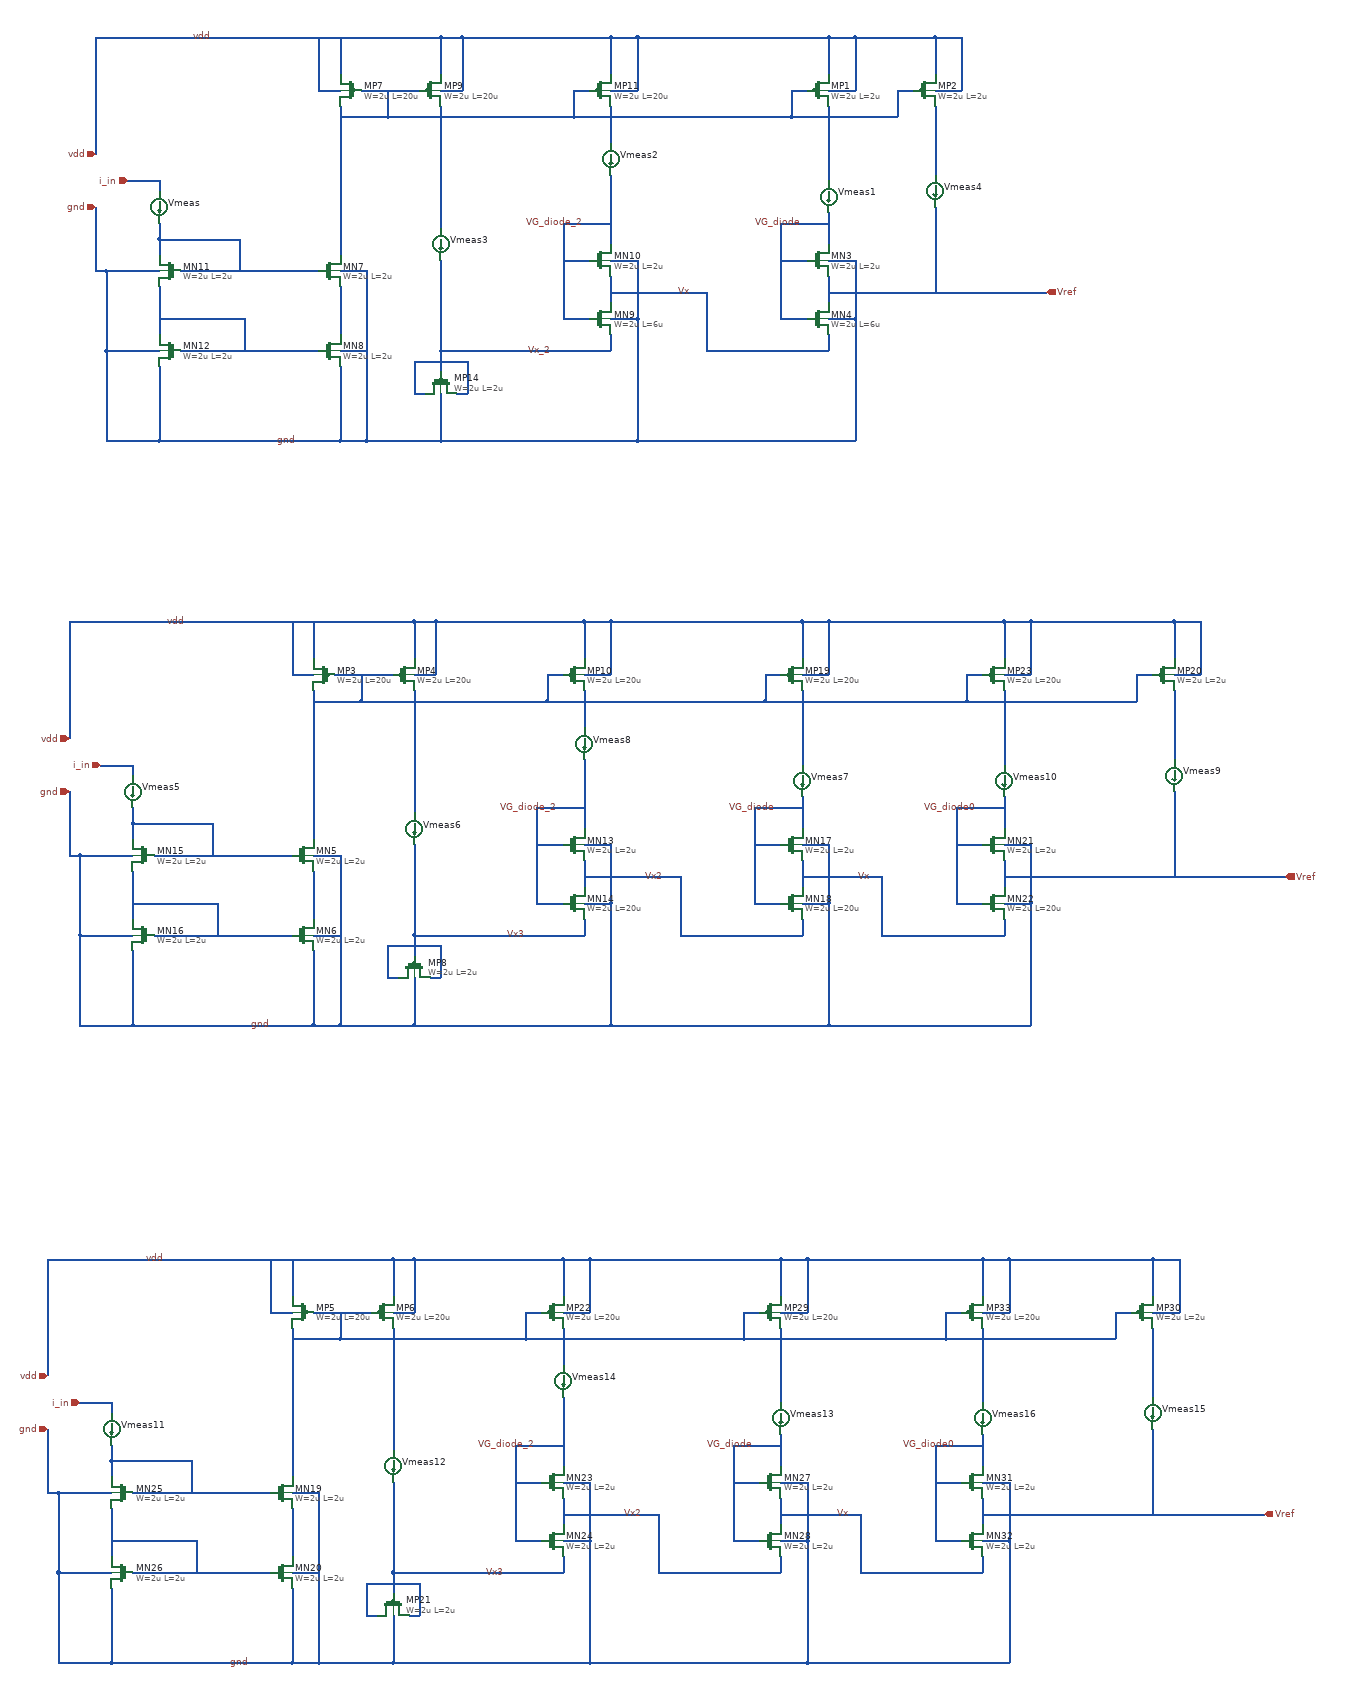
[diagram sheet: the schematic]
v {xschem version=3.4.0 file_version=1.2
}
G {}
K {}
V {}
S {}
E {}
N -300 -100 190 -100 {
lab=vdd}
N 190 -100 190 -30 {
lab=vdd}
N 0 -100 0 -30 {
lab=vdd}
N 40 0 150 0 {
lab=#net1}
N 0 30 0 90 {
lab=#net1}
N 190 30 190 90 {
lab=#net2}
N 90 0 90 40 {
lab=#net1}
N 90 40 90 50 {
lab=#net1}
N 0 50 90 50 {
lab=#net1}
N 0 150 0 310 {
lab=#net1}
N 0 370 0 460 {
lab=#net3}
N 0 520 0 660 {
lab=gnd}
N -260 660 0 660 {
lab=gnd}
N -300 340 -40 340 {
lab=#net4}
N -300 490 -40 490 {
lab=#net5}
N 0 340 50 340 {
lab=gnd}
N 50 340 50 660 {
lab=gnd}
N 0 660 50 660 {
lab=gnd}
N 0 490 50 490 {
lab=gnd}
N -40 0 0 0 {
lab=vdd}
N -40 -100 -40 0 {
lab=vdd}
N 190 0 230 0 {
lab=vdd}
N 230 -100 230 0 {
lab=vdd}
N 190 -100 230 -100 {
lab=vdd}
N 50 660 190 660 {
lab=gnd}
N 230 -100 510 -100 {
lab=vdd}
N 510 -100 510 -30 {
lab=vdd}
N 510 30 510 100 {
lab=#net6}
N 510 0 560 0 {
lab=vdd}
N 560 -100 560 0 {
lab=vdd}
N 510 -100 560 -100 {
lab=vdd}
N 440 0 470 0 {
lab=#net1}
N 440 0 440 50 {
lab=#net1}
N 420 430 470 430 {
lab=VG_diode_2}
N 420 250 420 430 {
lab=VG_diode_2}
N 420 250 510 250 {
lab=VG_diode_2}
N 420 320 470 320 {
lab=VG_diode_2}
N 510 350 510 400 {
lab=Vx}
N 510 460 510 490 {
lab=Vx_2}
N 190 660 560 660 {
lab=gnd}
N 510 430 560 430 {
lab=gnd}
N 510 320 560 320 {
lab=gnd}
N 560 320 560 430 {
lab=gnd}
N -340 370 -340 460 {
lab=#net5}
N -340 520 -340 660 {
lab=gnd}
N -340 660 -260 660 {
lab=gnd}
N -440 490 -340 490 {
lab=gnd}
N -440 490 -440 660 {
lab=gnd}
N -440 660 -340 660 {
lab=gnd}
N -440 340 -340 340 {
lab=gnd}
N -440 340 -440 490 {
lab=gnd}
N -340 -100 -300 -100 {
lab=vdd}
N -190 280 -190 340 {
lab=#net4}
N -340 280 -190 280 {
lab=#net4}
N -180 430 -180 490 {
lab=#net5}
N -340 430 -180 430 {
lab=#net5}
N 510 230 510 290 {
lab=VG_diode_2}
N -400 170 -340 170 {
lab=i_in}
N -460 -100 -460 120 {
lab=vdd}
N -460 -100 -340 -100 {
lab=vdd}
N -460 220 -460 340 {
lab=gnd}
N -460 340 -440 340 {
lab=gnd}
N -340 170 -340 190 {
lab=i_in}
N -340 250 -340 280 {
lab=#net4}
N -340 280 -340 310 {
lab=#net4}
N 190 150 190 260 {
lab=#net2}
N 190 320 190 490 {
lab=Vx_2}
N 190 490 190 530 {
lab=Vx_2}
N 220 570 240 570 {
lab=Vx_2}
N 240 510 240 570 {
lab=Vx_2}
N 190 510 240 510 {
lab=Vx_2}
N 140 570 160 570 {
lab=Vx_2}
N 140 510 140 570 {
lab=Vx_2}
N 140 510 190 510 {
lab=Vx_2}
N 190 570 190 660 {
lab=gnd}
N 90 50 440 50 {
lab=#net1}
N 920 -100 920 -30 {
lab=vdd}
N 920 30 920 100 {
lab=#net7}
N 920 0 970 0 {
lab=vdd}
N 970 -100 970 0 {
lab=vdd}
N 920 -100 970 -100 {
lab=vdd}
N 850 0 880 0 {
lab=#net1}
N 850 0 850 50 {
lab=#net1}
N 830 430 880 430 {
lab=VG_diode}
N 830 250 830 430 {
lab=VG_diode}
N 830 250 920 250 {
lab=VG_diode}
N 830 320 880 320 {
lab=VG_diode}
N 920 350 920 400 {
lab=Vref}
N 920 460 920 490 {
lab=Vx}
N 970 430 970 660 {
lab=gnd}
N 920 430 970 430 {
lab=gnd}
N 920 320 970 320 {
lab=gnd}
N 970 320 970 430 {
lab=gnd}
N 920 380 1330 380 {
lab=Vref}
N 920 150 920 170 {
lab=#net7}
N 920 230 920 290 {
lab=VG_diode}
N 440 50 850 50 {
lab=#net1}
N 190 490 510 490 {
lab=Vx_2}
N 560 430 560 660 {
lab=gnd}
N 560 660 970 660 {
lab=gnd}
N 690 490 920 490 {
lab=Vx}
N 690 380 690 490 {
lab=Vx}
N 510 380 690 380 {
lab=Vx}
N 510 160 510 230 {
lab=VG_diode_2}
N 190 90 190 150 {
lab=#net2}
N 0 90 0 140 {
lab=#net1}
N 0 140 0 150 {
lab=#net1}
N 920 100 920 150 {
lab=#net7}
N 560 -100 920 -100 {
lab=vdd}
N 1120 -100 1120 -30 {
lab=vdd}
N 1120 30 1120 100 {
lab=#net8}
N 1120 0 1170 0 {
lab=vdd}
N 1170 -100 1170 0 {
lab=vdd}
N 1120 -100 1170 -100 {
lab=vdd}
N 1050 0 1080 0 {
lab=#net1}
N 1050 0 1050 50 {
lab=#net1}
N 860 50 1050 50 {
lab=#net1}
N 850 50 860 50 {
lab=#net1}
N 970 -100 1120 -100 {
lab=vdd}
N 1120 100 1120 160 {
lab=#net8}
N 1120 220 1120 380 {
lab=Vref}
N -350 1000 140 1000 {
lab=vdd}
N 140 1000 140 1070 {
lab=vdd}
N -50 1000 -50 1070 {
lab=vdd}
N -10 1100 100 1100 {
lab=#net1}
N -50 1130 -50 1190 {
lab=#net1}
N 140 1130 140 1190 {
lab=#net2}
N 40 1100 40 1140 {
lab=#net1}
N 40 1140 40 1150 {
lab=#net1}
N -50 1150 40 1150 {
lab=#net1}
N -50 1250 -50 1410 {
lab=#net1}
N -50 1470 -50 1560 {
lab=#net3}
N -50 1620 -50 1760 {
lab=gnd}
N -310 1760 -50 1760 {
lab=gnd}
N -350 1440 -90 1440 {
lab=#net4}
N -350 1590 -90 1590 {
lab=#net5}
N -50 1440 0 1440 {
lab=gnd}
N 0 1440 0 1760 {
lab=gnd}
N -50 1760 0 1760 {
lab=gnd}
N -50 1590 0 1590 {
lab=gnd}
N -90 1100 -50 1100 {
lab=vdd}
N -90 1000 -90 1100 {
lab=vdd}
N 140 1100 180 1100 {
lab=vdd}
N 180 1000 180 1100 {
lab=vdd}
N 140 1000 180 1000 {
lab=vdd}
N 0 1760 140 1760 {
lab=gnd}
N 180 1000 460 1000 {
lab=vdd}
N 460 1000 460 1070 {
lab=vdd}
N 460 1130 460 1200 {
lab=#net6}
N 460 1100 510 1100 {
lab=vdd}
N 510 1000 510 1100 {
lab=vdd}
N 460 1000 510 1000 {
lab=vdd}
N 390 1100 420 1100 {
lab=#net1}
N 390 1100 390 1150 {
lab=#net1}
N 370 1530 420 1530 {
lab=VG_diode_2}
N 370 1350 370 1530 {
lab=VG_diode_2}
N 370 1350 460 1350 {
lab=VG_diode_2}
N 370 1420 420 1420 {
lab=VG_diode_2}
N 460 1450 460 1500 {
lab=Vx2}
N 460 1560 460 1590 {
lab=Vx3}
N 140 1760 510 1760 {
lab=gnd}
N 460 1530 510 1530 {
lab=gnd}
N 460 1420 510 1420 {
lab=gnd}
N 510 1420 510 1530 {
lab=gnd}
N -390 1470 -390 1560 {
lab=#net5}
N -390 1620 -390 1760 {
lab=gnd}
N -390 1760 -310 1760 {
lab=gnd}
N -490 1590 -390 1590 {
lab=gnd}
N -490 1590 -490 1760 {
lab=gnd}
N -490 1760 -390 1760 {
lab=gnd}
N -490 1440 -390 1440 {
lab=gnd}
N -490 1440 -490 1590 {
lab=gnd}
N -390 1000 -350 1000 {
lab=vdd}
N -240 1380 -240 1440 {
lab=#net4}
N -390 1380 -240 1380 {
lab=#net4}
N -230 1530 -230 1590 {
lab=#net5}
N -390 1530 -230 1530 {
lab=#net5}
N 460 1330 460 1390 {
lab=VG_diode_2}
N -450 1270 -390 1270 {
lab=i_in}
N -510 1000 -510 1220 {
lab=vdd}
N -510 1000 -390 1000 {
lab=vdd}
N -510 1320 -510 1440 {
lab=gnd}
N -510 1440 -490 1440 {
lab=gnd}
N -390 1270 -390 1290 {
lab=i_in}
N -390 1350 -390 1380 {
lab=#net4}
N -390 1380 -390 1410 {
lab=#net4}
N 140 1250 140 1360 {
lab=#net2}
N 140 1420 140 1590 {
lab=Vx3}
N 140 1590 140 1630 {
lab=Vx3}
N 170 1670 190 1670 {
lab=Vx3}
N 190 1610 190 1670 {
lab=Vx3}
N 140 1610 190 1610 {
lab=Vx3}
N 90 1670 110 1670 {
lab=Vx3}
N 90 1610 90 1670 {
lab=Vx3}
N 90 1610 140 1610 {
lab=Vx3}
N 140 1670 140 1760 {
lab=gnd}
N 40 1150 390 1150 {
lab=#net1}
N 870 1000 870 1070 {
lab=vdd}
N 870 1130 870 1200 {
lab=#net7}
N 870 1100 920 1100 {
lab=vdd}
N 920 1000 920 1100 {
lab=vdd}
N 870 1000 920 1000 {
lab=vdd}
N 800 1100 830 1100 {
lab=#net1}
N 800 1100 800 1150 {
lab=#net1}
N 780 1530 830 1530 {
lab=VG_diode}
N 780 1350 780 1530 {
lab=VG_diode}
N 780 1350 870 1350 {
lab=VG_diode}
N 780 1420 830 1420 {
lab=VG_diode}
N 870 1450 870 1500 {
lab=Vx}
N 870 1560 870 1590 {
lab=Vx2}
N 920 1530 920 1760 {
lab=gnd}
N 870 1530 920 1530 {
lab=gnd}
N 870 1420 920 1420 {
lab=gnd}
N 920 1420 920 1530 {
lab=gnd}
N 870 1250 870 1270 {
lab=#net7}
N 870 1330 870 1390 {
lab=VG_diode}
N 390 1150 800 1150 {
lab=#net1}
N 140 1590 460 1590 {
lab=Vx3}
N 510 1530 510 1760 {
lab=gnd}
N 510 1760 920 1760 {
lab=gnd}
N 640 1590 870 1590 {
lab=Vx2}
N 640 1480 640 1590 {
lab=Vx2}
N 460 1480 640 1480 {
lab=Vx2}
N 460 1260 460 1330 {
lab=VG_diode_2}
N 140 1190 140 1250 {
lab=#net2}
N -50 1190 -50 1240 {
lab=#net1}
N -50 1240 -50 1250 {
lab=#net1}
N 870 1200 870 1250 {
lab=#net7}
N 510 1000 870 1000 {
lab=vdd}
N 1570 1000 1570 1070 {
lab=vdd}
N 1570 1130 1570 1200 {
lab=#net8}
N 1570 1100 1620 1100 {
lab=vdd}
N 1620 1000 1620 1100 {
lab=vdd}
N 1570 1000 1620 1000 {
lab=vdd}
N 1500 1100 1530 1100 {
lab=#net1}
N 1500 1100 1500 1150 {
lab=#net1}
N 810 1150 1000 1150 {
lab=#net1}
N 800 1150 810 1150 {
lab=#net1}
N 920 1000 1070 1000 {
lab=vdd}
N 1570 1200 1570 1260 {
lab=#net8}
N 1570 1320 1570 1480 {
lab=Vref}
N 1020 1590 1250 1590 {
lab=Vx}
N 1020 1480 1020 1590 {
lab=Vx}
N 1300 1000 1450 1000 {
lab=vdd}
N 870 1480 1020 1480 {
lab=Vx}
N 920 1760 1300 1760 {
lab=gnd}
N 1070 1000 1250 1000 {
lab=vdd}
N 1000 1150 1180 1150 {
lab=#net1}
N 1450 1000 1570 1000 {
lab=vdd}
N 1380 1150 1500 1150 {
lab=#net1}
N 1250 1000 1250 1070 {
lab=vdd}
N 1250 1130 1250 1200 {
lab=#net9}
N 1250 1100 1300 1100 {
lab=vdd}
N 1300 1000 1300 1100 {
lab=vdd}
N 1250 1000 1300 1000 {
lab=vdd}
N 1180 1100 1210 1100 {
lab=#net1}
N 1180 1100 1180 1150 {
lab=#net1}
N 1160 1530 1210 1530 {
lab=VG_diode0}
N 1160 1350 1160 1530 {
lab=VG_diode0}
N 1160 1350 1250 1350 {
lab=VG_diode0}
N 1160 1420 1210 1420 {
lab=VG_diode0}
N 1250 1450 1250 1500 {
lab=Vref}
N 1250 1560 1250 1590 {
lab=Vx}
N 1300 1530 1300 1760 {
lab=gnd}
N 1250 1530 1300 1530 {
lab=gnd}
N 1250 1420 1300 1420 {
lab=gnd}
N 1300 1420 1300 1530 {
lab=gnd}
N 1250 1250 1250 1270 {
lab=#net9}
N 1250 1330 1250 1390 {
lab=VG_diode0}
N 1250 1200 1250 1250 {
lab=#net9}
N 1190 1150 1380 1150 {
lab=#net1}
N 1180 1150 1190 1150 {
lab=#net1}
N 1250 1480 1420 1480 {
lab=Vref}
N 1420 1480 1780 1480 {
lab=Vref}
N -390 2200 100 2200 {
lab=vdd}
N 100 2200 100 2270 {
lab=vdd}
N -90 2200 -90 2270 {
lab=vdd}
N -50 2300 60 2300 {
lab=#net1}
N -90 2330 -90 2390 {
lab=#net1}
N 100 2330 100 2390 {
lab=#net2}
N 0 2300 0 2340 {
lab=#net1}
N 0 2340 0 2350 {
lab=#net1}
N -90 2350 0 2350 {
lab=#net1}
N -90 2450 -90 2610 {
lab=#net1}
N -90 2670 -90 2760 {
lab=#net3}
N -90 2820 -90 2960 {
lab=gnd}
N -350 2960 -90 2960 {
lab=gnd}
N -390 2640 -130 2640 {
lab=#net4}
N -390 2790 -130 2790 {
lab=#net5}
N -90 2640 -40 2640 {
lab=gnd}
N -40 2640 -40 2960 {
lab=gnd}
N -90 2960 -40 2960 {
lab=gnd}
N -90 2790 -40 2790 {
lab=gnd}
N -130 2300 -90 2300 {
lab=vdd}
N -130 2200 -130 2300 {
lab=vdd}
N 100 2300 140 2300 {
lab=vdd}
N 140 2200 140 2300 {
lab=vdd}
N 100 2200 140 2200 {
lab=vdd}
N -40 2960 100 2960 {
lab=gnd}
N 140 2200 420 2200 {
lab=vdd}
N 420 2200 420 2270 {
lab=vdd}
N 420 2330 420 2400 {
lab=#net6}
N 420 2300 470 2300 {
lab=vdd}
N 470 2200 470 2300 {
lab=vdd}
N 420 2200 470 2200 {
lab=vdd}
N 350 2300 380 2300 {
lab=#net1}
N 350 2300 350 2350 {
lab=#net1}
N 330 2730 380 2730 {
lab=VG_diode_2}
N 330 2550 330 2730 {
lab=VG_diode_2}
N 330 2550 420 2550 {
lab=VG_diode_2}
N 330 2620 380 2620 {
lab=VG_diode_2}
N 420 2650 420 2700 {
lab=Vx2}
N 420 2760 420 2790 {
lab=Vx3}
N 100 2960 470 2960 {
lab=gnd}
N 420 2730 470 2730 {
lab=gnd}
N 420 2620 470 2620 {
lab=gnd}
N 470 2620 470 2730 {
lab=gnd}
N -430 2670 -430 2760 {
lab=#net5}
N -430 2820 -430 2960 {
lab=gnd}
N -430 2960 -350 2960 {
lab=gnd}
N -530 2790 -430 2790 {
lab=gnd}
N -530 2790 -530 2960 {
lab=gnd}
N -530 2960 -430 2960 {
lab=gnd}
N -530 2640 -430 2640 {
lab=gnd}
N -530 2640 -530 2790 {
lab=gnd}
N -430 2200 -390 2200 {
lab=vdd}
N -280 2580 -280 2640 {
lab=#net4}
N -430 2580 -280 2580 {
lab=#net4}
N -270 2730 -270 2790 {
lab=#net5}
N -430 2730 -270 2730 {
lab=#net5}
N 420 2530 420 2590 {
lab=VG_diode_2}
N -490 2470 -430 2470 {
lab=i_in}
N -550 2200 -550 2420 {
lab=vdd}
N -550 2200 -430 2200 {
lab=vdd}
N -550 2520 -550 2640 {
lab=gnd}
N -550 2640 -530 2640 {
lab=gnd}
N -430 2470 -430 2490 {
lab=i_in}
N -430 2550 -430 2580 {
lab=#net4}
N -430 2580 -430 2610 {
lab=#net4}
N 100 2450 100 2560 {
lab=#net2}
N 100 2620 100 2790 {
lab=Vx3}
N 100 2790 100 2830 {
lab=Vx3}
N 130 2870 150 2870 {
lab=Vx3}
N 150 2810 150 2870 {
lab=Vx3}
N 100 2810 150 2810 {
lab=Vx3}
N 50 2870 70 2870 {
lab=Vx3}
N 50 2810 50 2870 {
lab=Vx3}
N 50 2810 100 2810 {
lab=Vx3}
N 100 2870 100 2960 {
lab=gnd}
N 0 2350 350 2350 {
lab=#net1}
N 830 2200 830 2270 {
lab=vdd}
N 830 2330 830 2400 {
lab=#net7}
N 830 2300 880 2300 {
lab=vdd}
N 880 2200 880 2300 {
lab=vdd}
N 830 2200 880 2200 {
lab=vdd}
N 760 2300 790 2300 {
lab=#net1}
N 760 2300 760 2350 {
lab=#net1}
N 740 2730 790 2730 {
lab=VG_diode}
N 740 2550 740 2730 {
lab=VG_diode}
N 740 2550 830 2550 {
lab=VG_diode}
N 740 2620 790 2620 {
lab=VG_diode}
N 830 2650 830 2700 {
lab=Vx}
N 830 2760 830 2790 {
lab=Vx2}
N 880 2730 880 2960 {
lab=gnd}
N 830 2730 880 2730 {
lab=gnd}
N 830 2620 880 2620 {
lab=gnd}
N 880 2620 880 2730 {
lab=gnd}
N 830 2450 830 2470 {
lab=#net7}
N 830 2530 830 2590 {
lab=VG_diode}
N 350 2350 760 2350 {
lab=#net1}
N 100 2790 420 2790 {
lab=Vx3}
N 470 2730 470 2960 {
lab=gnd}
N 470 2960 880 2960 {
lab=gnd}
N 600 2790 830 2790 {
lab=Vx2}
N 600 2680 600 2790 {
lab=Vx2}
N 420 2680 600 2680 {
lab=Vx2}
N 420 2460 420 2530 {
lab=VG_diode_2}
N 100 2390 100 2450 {
lab=#net2}
N -90 2390 -90 2440 {
lab=#net1}
N -90 2440 -90 2450 {
lab=#net1}
N 830 2400 830 2450 {
lab=#net7}
N 470 2200 830 2200 {
lab=vdd}
N 1530 2200 1530 2270 {
lab=vdd}
N 1530 2330 1530 2400 {
lab=#net8}
N 1530 2300 1580 2300 {
lab=vdd}
N 1580 2200 1580 2300 {
lab=vdd}
N 1530 2200 1580 2200 {
lab=vdd}
N 1460 2300 1490 2300 {
lab=#net1}
N 1460 2300 1460 2350 {
lab=#net1}
N 770 2350 960 2350 {
lab=#net1}
N 760 2350 770 2350 {
lab=#net1}
N 880 2200 1030 2200 {
lab=vdd}
N 1530 2400 1530 2460 {
lab=#net8}
N 1530 2520 1530 2680 {
lab=Vref}
N 980 2790 1210 2790 {
lab=Vx}
N 980 2680 980 2790 {
lab=Vx}
N 1260 2200 1410 2200 {
lab=vdd}
N 830 2680 980 2680 {
lab=Vx}
N 880 2960 1260 2960 {
lab=gnd}
N 1030 2200 1210 2200 {
lab=vdd}
N 960 2350 1140 2350 {
lab=#net1}
N 1410 2200 1530 2200 {
lab=vdd}
N 1340 2350 1460 2350 {
lab=#net1}
N 1210 2200 1210 2270 {
lab=vdd}
N 1210 2330 1210 2400 {
lab=#net9}
N 1210 2300 1260 2300 {
lab=vdd}
N 1260 2200 1260 2300 {
lab=vdd}
N 1210 2200 1260 2200 {
lab=vdd}
N 1140 2300 1170 2300 {
lab=#net1}
N 1140 2300 1140 2350 {
lab=#net1}
N 1120 2730 1170 2730 {
lab=VG_diode0}
N 1120 2550 1120 2730 {
lab=VG_diode0}
N 1120 2550 1210 2550 {
lab=VG_diode0}
N 1120 2620 1170 2620 {
lab=VG_diode0}
N 1210 2650 1210 2700 {
lab=Vref}
N 1210 2760 1210 2790 {
lab=Vx}
N 1260 2730 1260 2960 {
lab=gnd}
N 1210 2730 1260 2730 {
lab=gnd}
N 1210 2620 1260 2620 {
lab=gnd}
N 1260 2620 1260 2730 {
lab=gnd}
N 1210 2450 1210 2470 {
lab=#net9}
N 1210 2530 1210 2590 {
lab=VG_diode0}
N 1210 2400 1210 2450 {
lab=#net9}
N 1150 2350 1340 2350 {
lab=#net1}
N 1140 2350 1150 2350 {
lab=#net1}
N 1210 2680 1380 2680 {
lab=Vref}
N 1380 2680 1740 2680 {
lab=Vref}
C {symbols/pfet_03v3.sym} 20 0 0 1 {name=MP7
L=20u
W=2u
nf=1
m=1
ad="'int((nf+1)/2) * W/nf * 0.18u'"
pd="'2*int((nf+1)/2) * (W/nf + 0.18u)'"
as="'int((nf+2)/2) * W/nf * 0.18u'"
ps="'2*int((nf+2)/2) * (W/nf + 0.18u)'"
nrd="'0.18u / W'" nrs="'0.18u / W'"
sa=0 sb=0 sd=0
model=pfet_03v3
spiceprefix=X
}
C {symbols/pfet_03v3.sym} 170 0 0 0 {name=MP9
L=20u
W=2u
nf=1
m=1
ad="'int((nf+1)/2) * W/nf * 0.18u'"
pd="'2*int((nf+1)/2) * (W/nf + 0.18u)'"
as="'int((nf+2)/2) * W/nf * 0.18u'"
ps="'2*int((nf+2)/2) * (W/nf + 0.18u)'"
nrd="'0.18u / W'" nrs="'0.18u / W'"
sa=0 sb=0 sd=0
model=pfet_03v3
spiceprefix=X
}
C {symbols/nfet_03v3.sym} -20 340 0 0 {name=MN7
L=2u
W=2u
nf=1
m=1
ad="'int((nf+1)/2) * W/nf * 0.18u'"
pd="'2*int((nf+1)/2) * (W/nf + 0.18u)'"
as="'int((nf+2)/2) * W/nf * 0.18u'"
ps="'2*int((nf+2)/2) * (W/nf + 0.18u)'"
nrd="'0.18u / W'" nrs="'0.18u / W'"
sa=0 sb=0 sd=0
model=nfet_03v3
spiceprefix=X
}
C {symbols/nfet_03v3.sym} -20 490 0 0 {name=MN8
L=2u
W=2u
nf=1
m=1
ad="'int((nf+1)/2) * W/nf * 0.18u'"
pd="'2*int((nf+1)/2) * (W/nf + 0.18u)'"
as="'int((nf+2)/2) * W/nf * 0.18u'"
ps="'2*int((nf+2)/2) * (W/nf + 0.18u)'"
nrd="'0.18u / W'" nrs="'0.18u / W'"
sa=0 sb=0 sd=0
model=nfet_03v3
spiceprefix=X
}
C {symbols/pfet_03v3.sym} 190 550 1 0 {name=MP14
L=2u
W=2u
nf=1
m=1
ad="'int((nf+1)/2) * W/nf * 0.18u'"
pd="'2*int((nf+1)/2) * (W/nf + 0.18u)'"
as="'int((nf+2)/2) * W/nf * 0.18u'"
ps="'2*int((nf+2)/2) * (W/nf + 0.18u)'"
nrd="'0.18u / W'" nrs="'0.18u / W'"
sa=0 sb=0 sd=0
model=pfet_03v3
spiceprefix=X
}
C {symbols/pfet_03v3.sym} 490 0 0 0 {name=MP11
L=20u
W=2u
nf=1
m=100
ad="'int((nf+1)/2) * W/nf * 0.18u'"
pd="'2*int((nf+1)/2) * (W/nf + 0.18u)'"
as="'int((nf+2)/2) * W/nf * 0.18u'"
ps="'2*int((nf+2)/2) * (W/nf + 0.18u)'"
nrd="'0.18u / W'" nrs="'0.18u / W'"
sa=0 sb=0 sd=0
model=pfet_03v3
spiceprefix=X
}
C {symbols/nfet_03v3.sym} 490 320 0 0 {name=MN10
L=2u
W=2u
nf=1
m=10
ad="'int((nf+1)/2) * W/nf * 0.18u'"
pd="'2*int((nf+1)/2) * (W/nf + 0.18u)'"
as="'int((nf+2)/2) * W/nf * 0.18u'"
ps="'2*int((nf+2)/2) * (W/nf + 0.18u)'"
nrd="'0.18u / W'" nrs="'0.18u / W'"
sa=0 sb=0 sd=0
model=nfet_03v3
spiceprefix=X
}
C {symbols/nfet_03v3.sym} 490 430 0 0 {name=MN9
L=6u
W=2u
nf=1
m=1
ad="'int((nf+1)/2) * W/nf * 0.18u'"
pd="'2*int((nf+1)/2) * (W/nf + 0.18u)'"
as="'int((nf+2)/2) * W/nf * 0.18u'"
ps="'2*int((nf+2)/2) * (W/nf + 0.18u)'"
nrd="'0.18u / W'" nrs="'0.18u / W'"
sa=0 sb=0 sd=0
model=nfet_03v3
spiceprefix=X
}
C {symbols/nfet_03v3.sym} -320 340 0 1 {name=MN11
L=2u
W=2u
nf=1
m=1
ad="'int((nf+1)/2) * W/nf * 0.18u'"
pd="'2*int((nf+1)/2) * (W/nf + 0.18u)'"
as="'int((nf+2)/2) * W/nf * 0.18u'"
ps="'2*int((nf+2)/2) * (W/nf + 0.18u)'"
nrd="'0.18u / W'" nrs="'0.18u / W'"
sa=0 sb=0 sd=0
model=nfet_03v3
spiceprefix=X
}
C {symbols/nfet_03v3.sym} -320 490 0 1 {name=MN12
L=2u
W=2u
nf=1
m=1
ad="'int((nf+1)/2) * W/nf * 0.18u'"
pd="'2*int((nf+1)/2) * (W/nf + 0.18u)'"
as="'int((nf+2)/2) * W/nf * 0.18u'"
ps="'2*int((nf+2)/2) * (W/nf + 0.18u)'"
nrd="'0.18u / W'" nrs="'0.18u / W'"
sa=0 sb=0 sd=0
model=nfet_03v3
spiceprefix=X
}
C {devices/lab_wire.sym} -240 -100 0 0 {name=p12 sig_type=std_logic lab=vdd}
C {devices/ammeter.sym} -340 220 0 0 {name=Vmeas}
C {devices/ammeter.sym} 190 290 0 0 {name=Vmeas3}
C {devices/lab_wire.sym} 460 250 0 0 {name=p4 sig_type=std_logic lab=VG_diode_2}
C {devices/iopin.sym} -400 170 2 0 {name=p5 lab=i_in}
C {devices/iopin.sym} -460 120 2 0 {name=p6 lab=vdd}
C {devices/lab_wire.sym} -80 660 0 0 {name=p7 sig_type=std_logic lab=gnd}
C {devices/iopin.sym} -460 220 2 0 {name=p8 lab=gnd}
C {symbols/nfet_03v3.sym} 900 320 0 0 {name=MN3
L=2u
W=2u
nf=1
m=10
ad="'int((nf+1)/2) * W/nf * 0.18u'"
pd="'2*int((nf+1)/2) * (W/nf + 0.18u)'"
as="'int((nf+2)/2) * W/nf * 0.18u'"
ps="'2*int((nf+2)/2) * (W/nf + 0.18u)'"
nrd="'0.18u / W'" nrs="'0.18u / W'"
sa=0 sb=0 sd=0
model=nfet_03v3
spiceprefix=X
}
C {symbols/nfet_03v3.sym} 900 430 0 0 {name=MN4
L=6u
W=2u
nf=1
m=1
ad="'int((nf+1)/2) * W/nf * 0.18u'"
pd="'2*int((nf+1)/2) * (W/nf + 0.18u)'"
as="'int((nf+2)/2) * W/nf * 0.18u'"
ps="'2*int((nf+2)/2) * (W/nf + 0.18u)'"
nrd="'0.18u / W'" nrs="'0.18u / W'"
sa=0 sb=0 sd=0
model=nfet_03v3
spiceprefix=X
}
C {devices/opin.sym} 1330 380 0 0 {name=p1 lab=Vref
W=2u}
C {devices/ammeter.sym} 920 200 0 0 {name=Vmeas1}
C {devices/lab_wire.sym} 870 250 0 0 {name=p9 sig_type=std_logic lab=VG_diode}
C {devices/lab_wire.sym} 660 380 0 0 {name=p2 sig_type=std_logic lab=Vx}
C {devices/lab_wire.sym} 400 490 0 0 {name=p3 sig_type=std_logic lab=Vx_2}
C {devices/ammeter.sym} 510 130 0 0 {name=Vmeas2}
C {symbols/pfet_03v3.sym} 900 0 0 0 {name=MP1
L=2u
W=2u
nf=1
m=30
ad="'int((nf+1)/2) * W/nf * 0.18u'"
pd="'2*int((nf+1)/2) * (W/nf + 0.18u)'"
as="'int((nf+2)/2) * W/nf * 0.18u'"
ps="'2*int((nf+2)/2) * (W/nf + 0.18u)'"
nrd="'0.18u / W'" nrs="'0.18u / W'"
sa=0 sb=0 sd=0
model=pfet_03v3
spiceprefix=X
}
C {symbols/pfet_03v3.sym} 1100 0 0 0 {name=MP2
L=2u
W=2u
nf=1
m=120
ad="'int((nf+1)/2) * W/nf * 0.18u'"
pd="'2*int((nf+1)/2) * (W/nf + 0.18u)'"
as="'int((nf+2)/2) * W/nf * 0.18u'"
ps="'2*int((nf+2)/2) * (W/nf + 0.18u)'"
nrd="'0.18u / W'" nrs="'0.18u / W'"
sa=0 sb=0 sd=0
model=pfet_03v3
spiceprefix=X
}
C {devices/ammeter.sym} 1120 190 0 0 {name=Vmeas4}
C {symbols/pfet_03v3.sym} -30 1100 0 1 {name=MP3
L=20u
W=2u
nf=1
m=1
ad="'int((nf+1)/2) * W/nf * 0.18u'"
pd="'2*int((nf+1)/2) * (W/nf + 0.18u)'"
as="'int((nf+2)/2) * W/nf * 0.18u'"
ps="'2*int((nf+2)/2) * (W/nf + 0.18u)'"
nrd="'0.18u / W'" nrs="'0.18u / W'"
sa=0 sb=0 sd=0
model=pfet_03v3
spiceprefix=X
}
C {symbols/pfet_03v3.sym} 120 1100 0 0 {name=MP4
L=20u
W=2u
nf=1
m=1
ad="'int((nf+1)/2) * W/nf * 0.18u'"
pd="'2*int((nf+1)/2) * (W/nf + 0.18u)'"
as="'int((nf+2)/2) * W/nf * 0.18u'"
ps="'2*int((nf+2)/2) * (W/nf + 0.18u)'"
nrd="'0.18u / W'" nrs="'0.18u / W'"
sa=0 sb=0 sd=0
model=pfet_03v3
spiceprefix=X
}
C {symbols/nfet_03v3.sym} -70 1440 0 0 {name=MN5
L=2u
W=2u
nf=1
m=1
ad="'int((nf+1)/2) * W/nf * 0.18u'"
pd="'2*int((nf+1)/2) * (W/nf + 0.18u)'"
as="'int((nf+2)/2) * W/nf * 0.18u'"
ps="'2*int((nf+2)/2) * (W/nf + 0.18u)'"
nrd="'0.18u / W'" nrs="'0.18u / W'"
sa=0 sb=0 sd=0
model=nfet_03v3
spiceprefix=X
}
C {symbols/nfet_03v3.sym} -70 1590 0 0 {name=MN6
L=2u
W=2u
nf=1
m=1
ad="'int((nf+1)/2) * W/nf * 0.18u'"
pd="'2*int((nf+1)/2) * (W/nf + 0.18u)'"
as="'int((nf+2)/2) * W/nf * 0.18u'"
ps="'2*int((nf+2)/2) * (W/nf + 0.18u)'"
nrd="'0.18u / W'" nrs="'0.18u / W'"
sa=0 sb=0 sd=0
model=nfet_03v3
spiceprefix=X
}
C {symbols/pfet_03v3.sym} 140 1650 1 0 {name=MP8
L=2u
W=2u
nf=1
m=1
ad="'int((nf+1)/2) * W/nf * 0.18u'"
pd="'2*int((nf+1)/2) * (W/nf + 0.18u)'"
as="'int((nf+2)/2) * W/nf * 0.18u'"
ps="'2*int((nf+2)/2) * (W/nf + 0.18u)'"
nrd="'0.18u / W'" nrs="'0.18u / W'"
sa=0 sb=0 sd=0
model=pfet_03v3
spiceprefix=X
}
C {symbols/pfet_03v3.sym} 440 1100 0 0 {name=MP10
L=20u
W=2u
nf=1
m=15
ad="'int((nf+1)/2) * W/nf * 0.18u'"
pd="'2*int((nf+1)/2) * (W/nf + 0.18u)'"
as="'int((nf+2)/2) * W/nf * 0.18u'"
ps="'2*int((nf+2)/2) * (W/nf + 0.18u)'"
nrd="'0.18u / W'" nrs="'0.18u / W'"
sa=0 sb=0 sd=0
model=pfet_03v3
spiceprefix=X
}
C {symbols/nfet_03v3.sym} 440 1420 0 0 {name=MN13
L=2u
W=2u
nf=1
m=100
ad="'int((nf+1)/2) * W/nf * 0.18u'"
pd="'2*int((nf+1)/2) * (W/nf + 0.18u)'"
as="'int((nf+2)/2) * W/nf * 0.18u'"
ps="'2*int((nf+2)/2) * (W/nf + 0.18u)'"
nrd="'0.18u / W'" nrs="'0.18u / W'"
sa=0 sb=0 sd=0
model=nfet_03v3
spiceprefix=X
}
C {symbols/nfet_03v3.sym} 440 1530 0 0 {name=MN14
L=20u
W=2u
nf=1
m=1
ad="'int((nf+1)/2) * W/nf * 0.18u'"
pd="'2*int((nf+1)/2) * (W/nf + 0.18u)'"
as="'int((nf+2)/2) * W/nf * 0.18u'"
ps="'2*int((nf+2)/2) * (W/nf + 0.18u)'"
nrd="'0.18u / W'" nrs="'0.18u / W'"
sa=0 sb=0 sd=0
model=nfet_03v3
spiceprefix=X
}
C {symbols/nfet_03v3.sym} -370 1440 0 1 {name=MN15
L=2u
W=2u
nf=1
m=1
ad="'int((nf+1)/2) * W/nf * 0.18u'"
pd="'2*int((nf+1)/2) * (W/nf + 0.18u)'"
as="'int((nf+2)/2) * W/nf * 0.18u'"
ps="'2*int((nf+2)/2) * (W/nf + 0.18u)'"
nrd="'0.18u / W'" nrs="'0.18u / W'"
sa=0 sb=0 sd=0
model=nfet_03v3
spiceprefix=X
}
C {symbols/nfet_03v3.sym} -370 1590 0 1 {name=MN16
L=2u
W=2u
nf=1
m=1
ad="'int((nf+1)/2) * W/nf * 0.18u'"
pd="'2*int((nf+1)/2) * (W/nf + 0.18u)'"
as="'int((nf+2)/2) * W/nf * 0.18u'"
ps="'2*int((nf+2)/2) * (W/nf + 0.18u)'"
nrd="'0.18u / W'" nrs="'0.18u / W'"
sa=0 sb=0 sd=0
model=nfet_03v3
spiceprefix=X
}
C {devices/lab_wire.sym} -290 1000 0 0 {name=p10 sig_type=std_logic lab=vdd}
C {devices/ammeter.sym} -390 1320 0 0 {name=Vmeas5}
C {devices/ammeter.sym} 140 1390 0 0 {name=Vmeas6}
C {devices/lab_wire.sym} 410 1350 0 0 {name=p11 sig_type=std_logic lab=VG_diode_2}
C {devices/iopin.sym} -450 1270 2 0 {name=p13 lab=i_in}
C {devices/iopin.sym} -510 1220 2 0 {name=p14 lab=vdd}
C {devices/lab_wire.sym} -130 1760 0 0 {name=p15 sig_type=std_logic lab=gnd}
C {devices/iopin.sym} -510 1320 2 0 {name=p16 lab=gnd}
C {symbols/nfet_03v3.sym} 850 1420 0 0 {name=MN17
L=2u
W=2u
nf=1
m=100
ad="'int((nf+1)/2) * W/nf * 0.18u'"
pd="'2*int((nf+1)/2) * (W/nf + 0.18u)'"
as="'int((nf+2)/2) * W/nf * 0.18u'"
ps="'2*int((nf+2)/2) * (W/nf + 0.18u)'"
nrd="'0.18u / W'" nrs="'0.18u / W'"
sa=0 sb=0 sd=0
model=nfet_03v3
spiceprefix=X
}
C {symbols/nfet_03v3.sym} 850 1530 0 0 {name=MN18
L=20u
W=2u
nf=1
m=1
ad="'int((nf+1)/2) * W/nf * 0.18u'"
pd="'2*int((nf+1)/2) * (W/nf + 0.18u)'"
as="'int((nf+2)/2) * W/nf * 0.18u'"
ps="'2*int((nf+2)/2) * (W/nf + 0.18u)'"
nrd="'0.18u / W'" nrs="'0.18u / W'"
sa=0 sb=0 sd=0
model=nfet_03v3
spiceprefix=X
}
C {devices/opin.sym} 1780 1480 0 0 {name=p17 lab=Vref
W=2u}
C {devices/ammeter.sym} 870 1300 0 0 {name=Vmeas7}
C {devices/lab_wire.sym} 820 1350 0 0 {name=p18 sig_type=std_logic lab=VG_diode}
C {devices/lab_wire.sym} 610 1480 0 0 {name=p19 sig_type=std_logic lab=Vx2}
C {devices/lab_wire.sym} 350 1590 0 0 {name=p20 sig_type=std_logic lab=Vx3}
C {devices/ammeter.sym} 460 1230 0 0 {name=Vmeas8}
C {symbols/pfet_03v3.sym} 850 1100 0 0 {name=MP19
L=20u
W=2u
nf=1
m=15
ad="'int((nf+1)/2) * W/nf * 0.18u'"
pd="'2*int((nf+1)/2) * (W/nf + 0.18u)'"
as="'int((nf+2)/2) * W/nf * 0.18u'"
ps="'2*int((nf+2)/2) * (W/nf + 0.18u)'"
nrd="'0.18u / W'" nrs="'0.18u / W'"
sa=0 sb=0 sd=0
model=pfet_03v3
spiceprefix=X
}
C {symbols/pfet_03v3.sym} 1550 1100 0 0 {name=MP20
L=2u
W=2u
nf=1
m=15
ad="'int((nf+1)/2) * W/nf * 0.18u'"
pd="'2*int((nf+1)/2) * (W/nf + 0.18u)'"
as="'int((nf+2)/2) * W/nf * 0.18u'"
ps="'2*int((nf+2)/2) * (W/nf + 0.18u)'"
nrd="'0.18u / W'" nrs="'0.18u / W'"
sa=0 sb=0 sd=0
model=pfet_03v3
spiceprefix=X
}
C {devices/ammeter.sym} 1570 1290 0 0 {name=Vmeas9}
C {devices/lab_wire.sym} 1000 1480 0 0 {name=p21 sig_type=std_logic lab=Vx}
C {symbols/nfet_03v3.sym} 1230 1420 0 0 {name=MN21
L=2u
W=2u
nf=1
m=100
ad="'int((nf+1)/2) * W/nf * 0.18u'"
pd="'2*int((nf+1)/2) * (W/nf + 0.18u)'"
as="'int((nf+2)/2) * W/nf * 0.18u'"
ps="'2*int((nf+2)/2) * (W/nf + 0.18u)'"
nrd="'0.18u / W'" nrs="'0.18u / W'"
sa=0 sb=0 sd=0
model=nfet_03v3
spiceprefix=X
}
C {symbols/nfet_03v3.sym} 1230 1530 0 0 {name=MN22
L=20u
W=2u
nf=1
m=1
ad="'int((nf+1)/2) * W/nf * 0.18u'"
pd="'2*int((nf+1)/2) * (W/nf + 0.18u)'"
as="'int((nf+2)/2) * W/nf * 0.18u'"
ps="'2*int((nf+2)/2) * (W/nf + 0.18u)'"
nrd="'0.18u / W'" nrs="'0.18u / W'"
sa=0 sb=0 sd=0
model=nfet_03v3
spiceprefix=X
}
C {devices/ammeter.sym} 1250 1300 0 0 {name=Vmeas10}
C {devices/lab_wire.sym} 1200 1350 0 0 {name=p22 sig_type=std_logic lab=VG_diode0}
C {symbols/pfet_03v3.sym} 1230 1100 0 0 {name=MP23
L=20u
W=2u
nf=1
m=15
ad="'int((nf+1)/2) * W/nf * 0.18u'"
pd="'2*int((nf+1)/2) * (W/nf + 0.18u)'"
as="'int((nf+2)/2) * W/nf * 0.18u'"
ps="'2*int((nf+2)/2) * (W/nf + 0.18u)'"
nrd="'0.18u / W'" nrs="'0.18u / W'"
sa=0 sb=0 sd=0
model=pfet_03v3
spiceprefix=X
}
C {symbols/pfet_03v3.sym} -70 2300 0 1 {name=MP5
L=20u
W=2u
nf=1
m=1
ad="'int((nf+1)/2) * W/nf * 0.18u'"
pd="'2*int((nf+1)/2) * (W/nf + 0.18u)'"
as="'int((nf+2)/2) * W/nf * 0.18u'"
ps="'2*int((nf+2)/2) * (W/nf + 0.18u)'"
nrd="'0.18u / W'" nrs="'0.18u / W'"
sa=0 sb=0 sd=0
model=pfet_03v3
spiceprefix=X
}
C {symbols/pfet_03v3.sym} 80 2300 0 0 {name=MP6
L=20u
W=2u
nf=1
m=1
ad="'int((nf+1)/2) * W/nf * 0.18u'"
pd="'2*int((nf+1)/2) * (W/nf + 0.18u)'"
as="'int((nf+2)/2) * W/nf * 0.18u'"
ps="'2*int((nf+2)/2) * (W/nf + 0.18u)'"
nrd="'0.18u / W'" nrs="'0.18u / W'"
sa=0 sb=0 sd=0
model=pfet_03v3
spiceprefix=X
}
C {symbols/nfet_03v3.sym} -110 2640 0 0 {name=MN19
L=2u
W=2u
nf=1
m=1
ad="'int((nf+1)/2) * W/nf * 0.18u'"
pd="'2*int((nf+1)/2) * (W/nf + 0.18u)'"
as="'int((nf+2)/2) * W/nf * 0.18u'"
ps="'2*int((nf+2)/2) * (W/nf + 0.18u)'"
nrd="'0.18u / W'" nrs="'0.18u / W'"
sa=0 sb=0 sd=0
model=nfet_03v3
spiceprefix=X
}
C {symbols/nfet_03v3.sym} -110 2790 0 0 {name=MN20
L=2u
W=2u
nf=1
m=1
ad="'int((nf+1)/2) * W/nf * 0.18u'"
pd="'2*int((nf+1)/2) * (W/nf + 0.18u)'"
as="'int((nf+2)/2) * W/nf * 0.18u'"
ps="'2*int((nf+2)/2) * (W/nf + 0.18u)'"
nrd="'0.18u / W'" nrs="'0.18u / W'"
sa=0 sb=0 sd=0
model=nfet_03v3
spiceprefix=X
}
C {symbols/pfet_03v3.sym} 100 2850 1 0 {name=MP21
L=2u
W=2u
nf=1
m=1
ad="'int((nf+1)/2) * W/nf * 0.18u'"
pd="'2*int((nf+1)/2) * (W/nf + 0.18u)'"
as="'int((nf+2)/2) * W/nf * 0.18u'"
ps="'2*int((nf+2)/2) * (W/nf + 0.18u)'"
nrd="'0.18u / W'" nrs="'0.18u / W'"
sa=0 sb=0 sd=0
model=pfet_03v3
spiceprefix=X
}
C {symbols/pfet_03v3.sym} 400 2300 0 0 {name=MP22
L=20u
W=2u
nf=1
m=1
ad="'int((nf+1)/2) * W/nf * 0.18u'"
pd="'2*int((nf+1)/2) * (W/nf + 0.18u)'"
as="'int((nf+2)/2) * W/nf * 0.18u'"
ps="'2*int((nf+2)/2) * (W/nf + 0.18u)'"
nrd="'0.18u / W'" nrs="'0.18u / W'"
sa=0 sb=0 sd=0
model=pfet_03v3
spiceprefix=X
}
C {symbols/nfet_03v3.sym} 400 2620 0 0 {name=MN23
L=2u
W=2u
nf=1
m=50
ad="'int((nf+1)/2) * W/nf * 0.18u'"
pd="'2*int((nf+1)/2) * (W/nf + 0.18u)'"
as="'int((nf+2)/2) * W/nf * 0.18u'"
ps="'2*int((nf+2)/2) * (W/nf + 0.18u)'"
nrd="'0.18u / W'" nrs="'0.18u / W'"
sa=0 sb=0 sd=0
model=nfet_03v3
spiceprefix=X
}
C {symbols/nfet_03v3.sym} 400 2730 0 0 {name=MN24
L=2u
W=2u
nf=1
m=10
ad="'int((nf+1)/2) * W/nf * 0.18u'"
pd="'2*int((nf+1)/2) * (W/nf + 0.18u)'"
as="'int((nf+2)/2) * W/nf * 0.18u'"
ps="'2*int((nf+2)/2) * (W/nf + 0.18u)'"
nrd="'0.18u / W'" nrs="'0.18u / W'"
sa=0 sb=0 sd=0
model=nfet_03v3
spiceprefix=X
}
C {symbols/nfet_03v3.sym} -410 2640 0 1 {name=MN25
L=2u
W=2u
nf=1
m=1
ad="'int((nf+1)/2) * W/nf * 0.18u'"
pd="'2*int((nf+1)/2) * (W/nf + 0.18u)'"
as="'int((nf+2)/2) * W/nf * 0.18u'"
ps="'2*int((nf+2)/2) * (W/nf + 0.18u)'"
nrd="'0.18u / W'" nrs="'0.18u / W'"
sa=0 sb=0 sd=0
model=nfet_03v3
spiceprefix=X
}
C {symbols/nfet_03v3.sym} -410 2790 0 1 {name=MN26
L=2u
W=2u
nf=1
m=1
ad="'int((nf+1)/2) * W/nf * 0.18u'"
pd="'2*int((nf+1)/2) * (W/nf + 0.18u)'"
as="'int((nf+2)/2) * W/nf * 0.18u'"
ps="'2*int((nf+2)/2) * (W/nf + 0.18u)'"
nrd="'0.18u / W'" nrs="'0.18u / W'"
sa=0 sb=0 sd=0
model=nfet_03v3
spiceprefix=X
}
C {devices/lab_wire.sym} -330 2200 0 0 {name=p23 sig_type=std_logic lab=vdd}
C {devices/ammeter.sym} -430 2520 0 0 {name=Vmeas11}
C {devices/ammeter.sym} 100 2590 0 0 {name=Vmeas12}
C {devices/lab_wire.sym} 370 2550 0 0 {name=p24 sig_type=std_logic lab=VG_diode_2}
C {devices/iopin.sym} -490 2470 2 0 {name=p25 lab=i_in}
C {devices/iopin.sym} -550 2420 2 0 {name=p26 lab=vdd}
C {devices/lab_wire.sym} -170 2960 0 0 {name=p27 sig_type=std_logic lab=gnd}
C {devices/iopin.sym} -550 2520 2 0 {name=p28 lab=gnd}
C {symbols/nfet_03v3.sym} 810 2620 0 0 {name=MN27
L=2u
W=2u
nf=1
m=50
ad="'int((nf+1)/2) * W/nf * 0.18u'"
pd="'2*int((nf+1)/2) * (W/nf + 0.18u)'"
as="'int((nf+2)/2) * W/nf * 0.18u'"
ps="'2*int((nf+2)/2) * (W/nf + 0.18u)'"
nrd="'0.18u / W'" nrs="'0.18u / W'"
sa=0 sb=0 sd=0
model=nfet_03v3
spiceprefix=X
}
C {symbols/nfet_03v3.sym} 810 2730 0 0 {name=MN28
L=2u
W=2u
nf=1
m=10
ad="'int((nf+1)/2) * W/nf * 0.18u'"
pd="'2*int((nf+1)/2) * (W/nf + 0.18u)'"
as="'int((nf+2)/2) * W/nf * 0.18u'"
ps="'2*int((nf+2)/2) * (W/nf + 0.18u)'"
nrd="'0.18u / W'" nrs="'0.18u / W'"
sa=0 sb=0 sd=0
model=nfet_03v3
spiceprefix=X
}
C {devices/opin.sym} 1740 2680 0 0 {name=p29 lab=Vref
W=2u}
C {devices/ammeter.sym} 830 2500 0 0 {name=Vmeas13}
C {devices/lab_wire.sym} 780 2550 0 0 {name=p30 sig_type=std_logic lab=VG_diode}
C {devices/lab_wire.sym} 570 2680 0 0 {name=p31 sig_type=std_logic lab=Vx2}
C {devices/lab_wire.sym} 310 2790 0 0 {name=p32 sig_type=std_logic lab=Vx3}
C {devices/ammeter.sym} 420 2430 0 0 {name=Vmeas14}
C {symbols/pfet_03v3.sym} 810 2300 0 0 {name=MP29
L=20u
W=2u
nf=1
m=1
ad="'int((nf+1)/2) * W/nf * 0.18u'"
pd="'2*int((nf+1)/2) * (W/nf + 0.18u)'"
as="'int((nf+2)/2) * W/nf * 0.18u'"
ps="'2*int((nf+2)/2) * (W/nf + 0.18u)'"
nrd="'0.18u / W'" nrs="'0.18u / W'"
sa=0 sb=0 sd=0
model=pfet_03v3
spiceprefix=X
}
C {symbols/pfet_03v3.sym} 1510 2300 0 0 {name=MP30
L=2u
W=2u
nf=1
m=50
ad="'int((nf+1)/2) * W/nf * 0.18u'"
pd="'2*int((nf+1)/2) * (W/nf + 0.18u)'"
as="'int((nf+2)/2) * W/nf * 0.18u'"
ps="'2*int((nf+2)/2) * (W/nf + 0.18u)'"
nrd="'0.18u / W'" nrs="'0.18u / W'"
sa=0 sb=0 sd=0
model=pfet_03v3
spiceprefix=X
}
C {devices/ammeter.sym} 1530 2490 0 0 {name=Vmeas15}
C {devices/lab_wire.sym} 960 2680 0 0 {name=p33 sig_type=std_logic lab=Vx}
C {symbols/nfet_03v3.sym} 1190 2620 0 0 {name=MN31
L=2u
W=2u
nf=1
m=50
ad="'int((nf+1)/2) * W/nf * 0.18u'"
pd="'2*int((nf+1)/2) * (W/nf + 0.18u)'"
as="'int((nf+2)/2) * W/nf * 0.18u'"
ps="'2*int((nf+2)/2) * (W/nf + 0.18u)'"
nrd="'0.18u / W'" nrs="'0.18u / W'"
sa=0 sb=0 sd=0
model=nfet_03v3
spiceprefix=X
}
C {symbols/nfet_03v3.sym} 1190 2730 0 0 {name=MN32
L=2u
W=2u
nf=1
m=10
ad="'int((nf+1)/2) * W/nf * 0.18u'"
pd="'2*int((nf+1)/2) * (W/nf + 0.18u)'"
as="'int((nf+2)/2) * W/nf * 0.18u'"
ps="'2*int((nf+2)/2) * (W/nf + 0.18u)'"
nrd="'0.18u / W'" nrs="'0.18u / W'"
sa=0 sb=0 sd=0
model=nfet_03v3
spiceprefix=X
}
C {devices/ammeter.sym} 1210 2500 0 0 {name=Vmeas16}
C {devices/lab_wire.sym} 1160 2550 0 0 {name=p34 sig_type=std_logic lab=VG_diode0}
C {symbols/pfet_03v3.sym} 1190 2300 0 0 {name=MP33
L=20u
W=2u
nf=1
m=1
ad="'int((nf+1)/2) * W/nf * 0.18u'"
pd="'2*int((nf+1)/2) * (W/nf + 0.18u)'"
as="'int((nf+2)/2) * W/nf * 0.18u'"
ps="'2*int((nf+2)/2) * (W/nf + 0.18u)'"
nrd="'0.18u / W'" nrs="'0.18u / W'"
sa=0 sb=0 sd=0
model=pfet_03v3
spiceprefix=X
}
